VERSION 5.7 ;
  NOWIREEXTENSIONATPIN ON ;
  DIVIDERCHAR "/" ;
  BUSBITCHARS "[]" ;
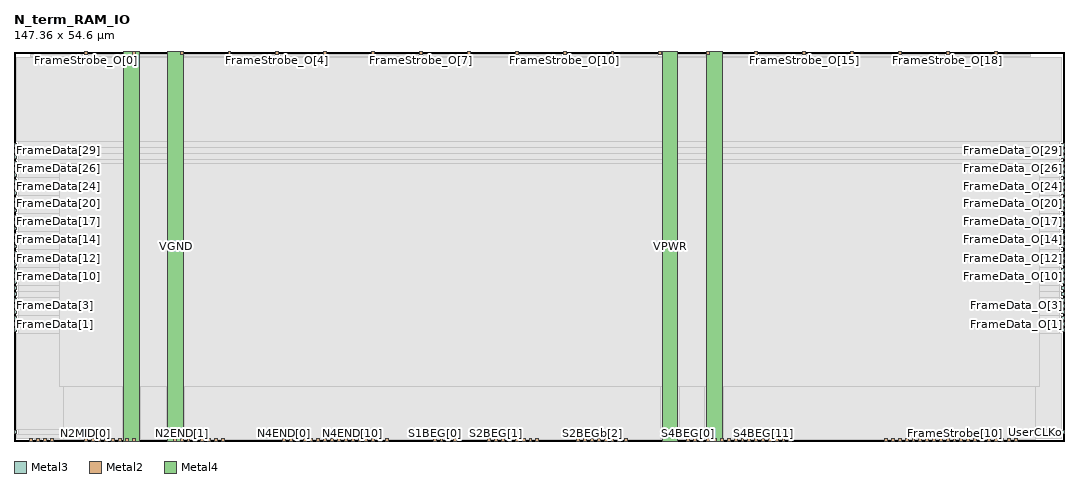
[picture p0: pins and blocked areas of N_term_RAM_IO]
MACRO N_term_RAM_IO
  CLASS BLOCK ;
  FOREIGN N_term_RAM_IO ;
  ORIGIN 0.000 0.000 ;
  SIZE 147.360 BY 54.600 ;
  PIN FrameData[0]
    DIRECTION INPUT ;
    USE SIGNAL ;
    ANTENNAGATEAREA 0.180700 ;
    ANTENNADIFFAREA 2.015400 ;
    PORT
      LAYER Metal3 ;
        RECT 0.000 15.340 0.400 15.740 ;
    END
  END FrameData[0]
  PIN FrameData[10]
    DIRECTION INPUT ;
    USE SIGNAL ;
    ANTENNAGATEAREA 0.180700 ;
    ANTENNADIFFAREA 2.015400 ;
    PORT
      LAYER Metal3 ;
        RECT 0.000 23.740 0.400 24.140 ;
    END
  END FrameData[10]
  PIN FrameData[11]
    DIRECTION INPUT ;
    USE SIGNAL ;
    ANTENNAGATEAREA 0.180700 ;
    ANTENNADIFFAREA 2.015400 ;
    PORT
      LAYER Metal3 ;
        RECT 0.000 24.580 0.400 24.980 ;
    END
  END FrameData[11]
  PIN FrameData[12]
    DIRECTION INPUT ;
    USE SIGNAL ;
    ANTENNAGATEAREA 0.180700 ;
    ANTENNADIFFAREA 2.015400 ;
    PORT
      LAYER Metal3 ;
        RECT 0.000 25.420 0.400 25.820 ;
    END
  END FrameData[12]
  PIN FrameData[13]
    DIRECTION INPUT ;
    USE SIGNAL ;
    ANTENNAGATEAREA 0.180700 ;
    ANTENNADIFFAREA 2.015400 ;
    PORT
      LAYER Metal3 ;
        RECT 0.000 26.260 0.400 26.660 ;
    END
  END FrameData[13]
  PIN FrameData[14]
    DIRECTION INPUT ;
    USE SIGNAL ;
    ANTENNAGATEAREA 0.180700 ;
    ANTENNADIFFAREA 2.015400 ;
    PORT
      LAYER Metal3 ;
        RECT 0.000 27.100 0.400 27.500 ;
    END
  END FrameData[14]
  PIN FrameData[15]
    DIRECTION INPUT ;
    USE SIGNAL ;
    ANTENNAGATEAREA 0.180700 ;
    ANTENNADIFFAREA 2.015400 ;
    PORT
      LAYER Metal3 ;
        RECT 0.000 27.940 0.400 28.340 ;
    END
  END FrameData[15]
  PIN FrameData[16]
    DIRECTION INPUT ;
    USE SIGNAL ;
    ANTENNAGATEAREA 0.180700 ;
    ANTENNADIFFAREA 2.015400 ;
    PORT
      LAYER Metal3 ;
        RECT 0.000 28.780 0.400 29.180 ;
    END
  END FrameData[16]
  PIN FrameData[17]
    DIRECTION INPUT ;
    USE SIGNAL ;
    ANTENNAGATEAREA 0.180700 ;
    ANTENNADIFFAREA 2.015400 ;
    PORT
      LAYER Metal3 ;
        RECT 0.000 29.620 0.400 30.020 ;
    END
  END FrameData[17]
  PIN FrameData[18]
    DIRECTION INPUT ;
    USE SIGNAL ;
    ANTENNAGATEAREA 0.180700 ;
    ANTENNADIFFAREA 2.015400 ;
    PORT
      LAYER Metal3 ;
        RECT 0.000 30.460 0.400 30.860 ;
    END
  END FrameData[18]
  PIN FrameData[19]
    DIRECTION INPUT ;
    USE SIGNAL ;
    ANTENNAGATEAREA 0.180700 ;
    ANTENNADIFFAREA 2.015400 ;
    PORT
      LAYER Metal3 ;
        RECT 0.000 31.300 0.400 31.700 ;
    END
  END FrameData[19]
  PIN FrameData[1]
    DIRECTION INPUT ;
    USE SIGNAL ;
    ANTENNAGATEAREA 0.180700 ;
    ANTENNADIFFAREA 2.015400 ;
    PORT
      LAYER Metal3 ;
        RECT 0.000 16.180 0.400 16.580 ;
    END
  END FrameData[1]
  PIN FrameData[20]
    DIRECTION INPUT ;
    USE SIGNAL ;
    ANTENNAGATEAREA 0.180700 ;
    ANTENNADIFFAREA 2.015400 ;
    PORT
      LAYER Metal3 ;
        RECT 0.000 32.140 0.400 32.540 ;
    END
  END FrameData[20]
  PIN FrameData[21]
    DIRECTION INPUT ;
    USE SIGNAL ;
    ANTENNAGATEAREA 0.180700 ;
    ANTENNADIFFAREA 2.015400 ;
    PORT
      LAYER Metal3 ;
        RECT 0.000 32.980 0.400 33.380 ;
    END
  END FrameData[21]
  PIN FrameData[22]
    DIRECTION INPUT ;
    USE SIGNAL ;
    ANTENNAGATEAREA 0.180700 ;
    ANTENNADIFFAREA 2.015400 ;
    PORT
      LAYER Metal3 ;
        RECT 0.000 33.820 0.400 34.220 ;
    END
  END FrameData[22]
  PIN FrameData[23]
    DIRECTION INPUT ;
    USE SIGNAL ;
    ANTENNAGATEAREA 0.180700 ;
    ANTENNADIFFAREA 2.015400 ;
    PORT
      LAYER Metal3 ;
        RECT 0.000 34.660 0.400 35.060 ;
    END
  END FrameData[23]
  PIN FrameData[24]
    DIRECTION INPUT ;
    USE SIGNAL ;
    ANTENNAGATEAREA 0.180700 ;
    ANTENNADIFFAREA 2.015400 ;
    PORT
      LAYER Metal3 ;
        RECT 0.000 35.500 0.400 35.900 ;
    END
  END FrameData[24]
  PIN FrameData[25]
    DIRECTION INPUT ;
    USE SIGNAL ;
    ANTENNAGATEAREA 0.180700 ;
    ANTENNADIFFAREA 2.015400 ;
    PORT
      LAYER Metal3 ;
        RECT 0.000 36.340 0.400 36.740 ;
    END
  END FrameData[25]
  PIN FrameData[26]
    DIRECTION INPUT ;
    USE SIGNAL ;
    ANTENNAGATEAREA 0.180700 ;
    ANTENNADIFFAREA 2.015400 ;
    PORT
      LAYER Metal3 ;
        RECT 0.000 37.180 0.400 37.580 ;
    END
  END FrameData[26]
  PIN FrameData[27]
    DIRECTION INPUT ;
    USE SIGNAL ;
    ANTENNAGATEAREA 0.180700 ;
    ANTENNADIFFAREA 2.015400 ;
    PORT
      LAYER Metal3 ;
        RECT 0.000 38.020 0.400 38.420 ;
    END
  END FrameData[27]
  PIN FrameData[28]
    DIRECTION INPUT ;
    USE SIGNAL ;
    ANTENNAGATEAREA 0.180700 ;
    ANTENNADIFFAREA 2.015400 ;
    PORT
      LAYER Metal3 ;
        RECT 0.000 38.860 0.400 39.260 ;
    END
  END FrameData[28]
  PIN FrameData[29]
    DIRECTION INPUT ;
    USE SIGNAL ;
    ANTENNAGATEAREA 0.180700 ;
    ANTENNADIFFAREA 2.015400 ;
    PORT
      LAYER Metal3 ;
        RECT 0.000 39.700 0.400 40.100 ;
    END
  END FrameData[29]
  PIN FrameData[2]
    DIRECTION INPUT ;
    USE SIGNAL ;
    ANTENNAGATEAREA 0.180700 ;
    ANTENNADIFFAREA 2.015400 ;
    PORT
      LAYER Metal3 ;
        RECT 0.000 17.020 0.400 17.420 ;
    END
  END FrameData[2]
  PIN FrameData[30]
    DIRECTION INPUT ;
    USE SIGNAL ;
    ANTENNAGATEAREA 0.180700 ;
    ANTENNADIFFAREA 2.015400 ;
    PORT
      LAYER Metal3 ;
        RECT 0.000 40.540 0.400 40.940 ;
    END
  END FrameData[30]
  PIN FrameData[31]
    DIRECTION INPUT ;
    USE SIGNAL ;
    ANTENNAGATEAREA 0.180700 ;
    ANTENNADIFFAREA 2.015400 ;
    PORT
      LAYER Metal3 ;
        RECT 0.000 41.380 0.400 41.780 ;
    END
  END FrameData[31]
  PIN FrameData[3]
    DIRECTION INPUT ;
    USE SIGNAL ;
    ANTENNAGATEAREA 0.180700 ;
    ANTENNADIFFAREA 2.015400 ;
    PORT
      LAYER Metal3 ;
        RECT 0.000 17.860 0.400 18.260 ;
    END
  END FrameData[3]
  PIN FrameData[4]
    DIRECTION INPUT ;
    USE SIGNAL ;
    ANTENNAGATEAREA 0.180700 ;
    ANTENNADIFFAREA 2.015400 ;
    PORT
      LAYER Metal3 ;
        RECT 0.000 18.700 0.400 19.100 ;
    END
  END FrameData[4]
  PIN FrameData[5]
    DIRECTION INPUT ;
    USE SIGNAL ;
    ANTENNAGATEAREA 0.180700 ;
    ANTENNADIFFAREA 2.015400 ;
    PORT
      LAYER Metal3 ;
        RECT 0.000 19.540 0.400 19.940 ;
    END
  END FrameData[5]
  PIN FrameData[6]
    DIRECTION INPUT ;
    USE SIGNAL ;
    ANTENNAGATEAREA 0.180700 ;
    ANTENNADIFFAREA 2.015400 ;
    PORT
      LAYER Metal3 ;
        RECT 0.000 20.380 0.400 20.780 ;
    END
  END FrameData[6]
  PIN FrameData[7]
    DIRECTION INPUT ;
    USE SIGNAL ;
    ANTENNAGATEAREA 0.180700 ;
    ANTENNADIFFAREA 2.015400 ;
    PORT
      LAYER Metal3 ;
        RECT 0.000 21.220 0.400 21.620 ;
    END
  END FrameData[7]
  PIN FrameData[8]
    DIRECTION INPUT ;
    USE SIGNAL ;
    ANTENNAGATEAREA 0.180700 ;
    ANTENNADIFFAREA 2.015400 ;
    PORT
      LAYER Metal3 ;
        RECT 0.000 22.060 0.400 22.460 ;
    END
  END FrameData[8]
  PIN FrameData[9]
    DIRECTION INPUT ;
    USE SIGNAL ;
    ANTENNAGATEAREA 0.180700 ;
    ANTENNADIFFAREA 2.015400 ;
    PORT
      LAYER Metal3 ;
        RECT 0.000 22.900 0.400 23.300 ;
    END
  END FrameData[9]
  PIN FrameData_O[0]
    DIRECTION OUTPUT ;
    USE SIGNAL ;
    ANTENNADIFFAREA 2.724000 ;
    PORT
      LAYER Metal3 ;
        RECT 146.960 15.340 147.360 15.740 ;
    END
  END FrameData_O[0]
  PIN FrameData_O[10]
    DIRECTION OUTPUT ;
    USE SIGNAL ;
    ANTENNADIFFAREA 2.724000 ;
    PORT
      LAYER Metal3 ;
        RECT 146.960 23.740 147.360 24.140 ;
    END
  END FrameData_O[10]
  PIN FrameData_O[11]
    DIRECTION OUTPUT ;
    USE SIGNAL ;
    ANTENNADIFFAREA 2.724000 ;
    PORT
      LAYER Metal3 ;
        RECT 146.960 24.580 147.360 24.980 ;
    END
  END FrameData_O[11]
  PIN FrameData_O[12]
    DIRECTION OUTPUT ;
    USE SIGNAL ;
    ANTENNADIFFAREA 2.724000 ;
    PORT
      LAYER Metal3 ;
        RECT 146.960 25.420 147.360 25.820 ;
    END
  END FrameData_O[12]
  PIN FrameData_O[13]
    DIRECTION OUTPUT ;
    USE SIGNAL ;
    ANTENNADIFFAREA 2.724000 ;
    PORT
      LAYER Metal3 ;
        RECT 146.960 26.260 147.360 26.660 ;
    END
  END FrameData_O[13]
  PIN FrameData_O[14]
    DIRECTION OUTPUT ;
    USE SIGNAL ;
    ANTENNADIFFAREA 2.724000 ;
    PORT
      LAYER Metal3 ;
        RECT 146.960 27.100 147.360 27.500 ;
    END
  END FrameData_O[14]
  PIN FrameData_O[15]
    DIRECTION OUTPUT ;
    USE SIGNAL ;
    ANTENNADIFFAREA 2.724000 ;
    PORT
      LAYER Metal3 ;
        RECT 146.960 27.940 147.360 28.340 ;
    END
  END FrameData_O[15]
  PIN FrameData_O[16]
    DIRECTION OUTPUT ;
    USE SIGNAL ;
    ANTENNADIFFAREA 2.724000 ;
    PORT
      LAYER Metal3 ;
        RECT 146.960 28.780 147.360 29.180 ;
    END
  END FrameData_O[16]
  PIN FrameData_O[17]
    DIRECTION OUTPUT ;
    USE SIGNAL ;
    ANTENNADIFFAREA 2.724000 ;
    PORT
      LAYER Metal3 ;
        RECT 146.960 29.620 147.360 30.020 ;
    END
  END FrameData_O[17]
  PIN FrameData_O[18]
    DIRECTION OUTPUT ;
    USE SIGNAL ;
    ANTENNADIFFAREA 2.724000 ;
    PORT
      LAYER Metal3 ;
        RECT 146.960 30.460 147.360 30.860 ;
    END
  END FrameData_O[18]
  PIN FrameData_O[19]
    DIRECTION OUTPUT ;
    USE SIGNAL ;
    ANTENNADIFFAREA 2.724000 ;
    PORT
      LAYER Metal3 ;
        RECT 146.960 31.300 147.360 31.700 ;
    END
  END FrameData_O[19]
  PIN FrameData_O[1]
    DIRECTION OUTPUT ;
    USE SIGNAL ;
    ANTENNADIFFAREA 2.724000 ;
    PORT
      LAYER Metal3 ;
        RECT 146.960 16.180 147.360 16.580 ;
    END
  END FrameData_O[1]
  PIN FrameData_O[20]
    DIRECTION OUTPUT ;
    USE SIGNAL ;
    ANTENNADIFFAREA 2.724000 ;
    PORT
      LAYER Metal3 ;
        RECT 146.960 32.140 147.360 32.540 ;
    END
  END FrameData_O[20]
  PIN FrameData_O[21]
    DIRECTION OUTPUT ;
    USE SIGNAL ;
    ANTENNADIFFAREA 2.724000 ;
    PORT
      LAYER Metal3 ;
        RECT 146.960 32.980 147.360 33.380 ;
    END
  END FrameData_O[21]
  PIN FrameData_O[22]
    DIRECTION OUTPUT ;
    USE SIGNAL ;
    ANTENNADIFFAREA 2.724000 ;
    PORT
      LAYER Metal3 ;
        RECT 146.960 33.820 147.360 34.220 ;
    END
  END FrameData_O[22]
  PIN FrameData_O[23]
    DIRECTION OUTPUT ;
    USE SIGNAL ;
    ANTENNADIFFAREA 2.724000 ;
    PORT
      LAYER Metal3 ;
        RECT 146.960 34.660 147.360 35.060 ;
    END
  END FrameData_O[23]
  PIN FrameData_O[24]
    DIRECTION OUTPUT ;
    USE SIGNAL ;
    ANTENNADIFFAREA 2.724000 ;
    PORT
      LAYER Metal3 ;
        RECT 146.960 35.500 147.360 35.900 ;
    END
  END FrameData_O[24]
  PIN FrameData_O[25]
    DIRECTION OUTPUT ;
    USE SIGNAL ;
    ANTENNADIFFAREA 2.724000 ;
    PORT
      LAYER Metal3 ;
        RECT 146.960 36.340 147.360 36.740 ;
    END
  END FrameData_O[25]
  PIN FrameData_O[26]
    DIRECTION OUTPUT ;
    USE SIGNAL ;
    ANTENNADIFFAREA 2.724000 ;
    PORT
      LAYER Metal3 ;
        RECT 146.960 37.180 147.360 37.580 ;
    END
  END FrameData_O[26]
  PIN FrameData_O[27]
    DIRECTION OUTPUT ;
    USE SIGNAL ;
    ANTENNADIFFAREA 2.724000 ;
    PORT
      LAYER Metal3 ;
        RECT 146.960 38.020 147.360 38.420 ;
    END
  END FrameData_O[27]
  PIN FrameData_O[28]
    DIRECTION OUTPUT ;
    USE SIGNAL ;
    ANTENNADIFFAREA 2.724000 ;
    PORT
      LAYER Metal3 ;
        RECT 146.960 38.860 147.360 39.260 ;
    END
  END FrameData_O[28]
  PIN FrameData_O[29]
    DIRECTION OUTPUT ;
    USE SIGNAL ;
    ANTENNADIFFAREA 2.724000 ;
    PORT
      LAYER Metal3 ;
        RECT 146.960 39.700 147.360 40.100 ;
    END
  END FrameData_O[29]
  PIN FrameData_O[2]
    DIRECTION OUTPUT ;
    USE SIGNAL ;
    ANTENNADIFFAREA 2.724000 ;
    PORT
      LAYER Metal3 ;
        RECT 146.960 17.020 147.360 17.420 ;
    END
  END FrameData_O[2]
  PIN FrameData_O[30]
    DIRECTION OUTPUT ;
    USE SIGNAL ;
    ANTENNADIFFAREA 2.724000 ;
    PORT
      LAYER Metal3 ;
        RECT 146.960 40.540 147.360 40.940 ;
    END
  END FrameData_O[30]
  PIN FrameData_O[31]
    DIRECTION OUTPUT ;
    USE SIGNAL ;
    ANTENNADIFFAREA 2.724000 ;
    PORT
      LAYER Metal3 ;
        RECT 146.960 41.380 147.360 41.780 ;
    END
  END FrameData_O[31]
  PIN FrameData_O[3]
    DIRECTION OUTPUT ;
    USE SIGNAL ;
    ANTENNADIFFAREA 2.724000 ;
    PORT
      LAYER Metal3 ;
        RECT 146.960 17.860 147.360 18.260 ;
    END
  END FrameData_O[3]
  PIN FrameData_O[4]
    DIRECTION OUTPUT ;
    USE SIGNAL ;
    ANTENNADIFFAREA 2.724000 ;
    PORT
      LAYER Metal3 ;
        RECT 146.960 18.700 147.360 19.100 ;
    END
  END FrameData_O[4]
  PIN FrameData_O[5]
    DIRECTION OUTPUT ;
    USE SIGNAL ;
    ANTENNADIFFAREA 2.724000 ;
    PORT
      LAYER Metal3 ;
        RECT 146.960 19.540 147.360 19.940 ;
    END
  END FrameData_O[5]
  PIN FrameData_O[6]
    DIRECTION OUTPUT ;
    USE SIGNAL ;
    ANTENNADIFFAREA 2.724000 ;
    PORT
      LAYER Metal3 ;
        RECT 146.960 20.380 147.360 20.780 ;
    END
  END FrameData_O[6]
  PIN FrameData_O[7]
    DIRECTION OUTPUT ;
    USE SIGNAL ;
    ANTENNADIFFAREA 2.724000 ;
    PORT
      LAYER Metal3 ;
        RECT 146.960 21.220 147.360 21.620 ;
    END
  END FrameData_O[7]
  PIN FrameData_O[8]
    DIRECTION OUTPUT ;
    USE SIGNAL ;
    ANTENNADIFFAREA 2.724000 ;
    PORT
      LAYER Metal3 ;
        RECT 146.960 22.060 147.360 22.460 ;
    END
  END FrameData_O[8]
  PIN FrameData_O[9]
    DIRECTION OUTPUT ;
    USE SIGNAL ;
    ANTENNADIFFAREA 2.724000 ;
    PORT
      LAYER Metal3 ;
        RECT 146.960 22.900 147.360 23.300 ;
    END
  END FrameData_O[9]
  PIN FrameStrobe[0]
    DIRECTION INPUT ;
    USE SIGNAL ;
    ANTENNAGATEAREA 0.180700 ;
    ANTENNADIFFAREA 2.015400 ;
    PORT
      LAYER Metal2 ;
        RECT 122.200 0.000 122.600 0.400 ;
    END
  END FrameStrobe[0]
  PIN FrameStrobe[10]
    DIRECTION INPUT ;
    USE SIGNAL ;
    ANTENNAGATEAREA 0.180700 ;
    ANTENNADIFFAREA 2.015400 ;
    PORT
      LAYER Metal2 ;
        RECT 131.800 0.000 132.200 0.400 ;
    END
  END FrameStrobe[10]
  PIN FrameStrobe[11]
    DIRECTION INPUT ;
    USE SIGNAL ;
    ANTENNAGATEAREA 0.180700 ;
    ANTENNADIFFAREA 2.015400 ;
    PORT
      LAYER Metal2 ;
        RECT 132.760 0.000 133.160 0.400 ;
    END
  END FrameStrobe[11]
  PIN FrameStrobe[12]
    DIRECTION INPUT ;
    USE SIGNAL ;
    ANTENNAGATEAREA 0.180700 ;
    ANTENNADIFFAREA 2.015400 ;
    PORT
      LAYER Metal2 ;
        RECT 133.720 0.000 134.120 0.400 ;
    END
  END FrameStrobe[12]
  PIN FrameStrobe[13]
    DIRECTION INPUT ;
    USE SIGNAL ;
    ANTENNAGATEAREA 0.180700 ;
    ANTENNADIFFAREA 2.015400 ;
    PORT
      LAYER Metal2 ;
        RECT 134.680 0.000 135.080 0.400 ;
    END
  END FrameStrobe[13]
  PIN FrameStrobe[14]
    DIRECTION INPUT ;
    USE SIGNAL ;
    ANTENNAGATEAREA 0.180700 ;
    ANTENNADIFFAREA 2.015400 ;
    PORT
      LAYER Metal2 ;
        RECT 135.640 0.000 136.040 0.400 ;
    END
  END FrameStrobe[14]
  PIN FrameStrobe[15]
    DIRECTION INPUT ;
    USE SIGNAL ;
    ANTENNAGATEAREA 0.180700 ;
    ANTENNADIFFAREA 2.015400 ;
    PORT
      LAYER Metal2 ;
        RECT 136.600 0.000 137.000 0.400 ;
    END
  END FrameStrobe[15]
  PIN FrameStrobe[16]
    DIRECTION INPUT ;
    USE SIGNAL ;
    ANTENNAGATEAREA 0.180700 ;
    ANTENNADIFFAREA 2.015400 ;
    PORT
      LAYER Metal2 ;
        RECT 137.560 0.000 137.960 0.400 ;
    END
  END FrameStrobe[16]
  PIN FrameStrobe[17]
    DIRECTION INPUT ;
    USE SIGNAL ;
    ANTENNAGATEAREA 0.180700 ;
    ANTENNADIFFAREA 2.015400 ;
    PORT
      LAYER Metal2 ;
        RECT 138.520 0.000 138.920 0.400 ;
    END
  END FrameStrobe[17]
  PIN FrameStrobe[18]
    DIRECTION INPUT ;
    USE SIGNAL ;
    ANTENNAGATEAREA 0.180700 ;
    ANTENNADIFFAREA 2.015400 ;
    PORT
      LAYER Metal2 ;
        RECT 139.480 0.000 139.880 0.400 ;
    END
  END FrameStrobe[18]
  PIN FrameStrobe[19]
    DIRECTION INPUT ;
    USE SIGNAL ;
    ANTENNAGATEAREA 0.180700 ;
    ANTENNADIFFAREA 2.015400 ;
    PORT
      LAYER Metal2 ;
        RECT 140.440 0.000 140.840 0.400 ;
    END
  END FrameStrobe[19]
  PIN FrameStrobe[1]
    DIRECTION INPUT ;
    USE SIGNAL ;
    ANTENNAGATEAREA 0.180700 ;
    ANTENNADIFFAREA 2.015400 ;
    PORT
      LAYER Metal2 ;
        RECT 123.160 0.000 123.560 0.400 ;
    END
  END FrameStrobe[1]
  PIN FrameStrobe[2]
    DIRECTION INPUT ;
    USE SIGNAL ;
    ANTENNAGATEAREA 0.180700 ;
    ANTENNADIFFAREA 2.015400 ;
    PORT
      LAYER Metal2 ;
        RECT 124.120 0.000 124.520 0.400 ;
    END
  END FrameStrobe[2]
  PIN FrameStrobe[3]
    DIRECTION INPUT ;
    USE SIGNAL ;
    ANTENNAGATEAREA 0.180700 ;
    ANTENNADIFFAREA 2.015400 ;
    PORT
      LAYER Metal2 ;
        RECT 125.080 0.000 125.480 0.400 ;
    END
  END FrameStrobe[3]
  PIN FrameStrobe[4]
    DIRECTION INPUT ;
    USE SIGNAL ;
    ANTENNAGATEAREA 0.180700 ;
    ANTENNADIFFAREA 2.015400 ;
    PORT
      LAYER Metal2 ;
        RECT 126.040 0.000 126.440 0.400 ;
    END
  END FrameStrobe[4]
  PIN FrameStrobe[5]
    DIRECTION INPUT ;
    USE SIGNAL ;
    ANTENNAGATEAREA 0.180700 ;
    ANTENNADIFFAREA 2.015400 ;
    PORT
      LAYER Metal2 ;
        RECT 127.000 0.000 127.400 0.400 ;
    END
  END FrameStrobe[5]
  PIN FrameStrobe[6]
    DIRECTION INPUT ;
    USE SIGNAL ;
    ANTENNAGATEAREA 0.180700 ;
    ANTENNADIFFAREA 2.015400 ;
    PORT
      LAYER Metal2 ;
        RECT 127.960 0.000 128.360 0.400 ;
    END
  END FrameStrobe[6]
  PIN FrameStrobe[7]
    DIRECTION INPUT ;
    USE SIGNAL ;
    ANTENNAGATEAREA 0.180700 ;
    ANTENNADIFFAREA 2.015400 ;
    PORT
      LAYER Metal2 ;
        RECT 128.920 0.000 129.320 0.400 ;
    END
  END FrameStrobe[7]
  PIN FrameStrobe[8]
    DIRECTION INPUT ;
    USE SIGNAL ;
    ANTENNAGATEAREA 0.180700 ;
    ANTENNADIFFAREA 2.015400 ;
    PORT
      LAYER Metal2 ;
        RECT 129.880 0.000 130.280 0.400 ;
    END
  END FrameStrobe[8]
  PIN FrameStrobe[9]
    DIRECTION INPUT ;
    USE SIGNAL ;
    ANTENNAGATEAREA 0.180700 ;
    ANTENNADIFFAREA 2.015400 ;
    PORT
      LAYER Metal2 ;
        RECT 130.840 0.000 131.240 0.400 ;
    END
  END FrameStrobe[9]
  PIN FrameStrobe_O[0]
    DIRECTION OUTPUT ;
    USE SIGNAL ;
    ANTENNADIFFAREA 2.724000 ;
    PORT
      LAYER Metal2 ;
        RECT 9.880 54.200 10.280 54.600 ;
    END
  END FrameStrobe_O[0]
  PIN FrameStrobe_O[10]
    DIRECTION OUTPUT ;
    USE SIGNAL ;
    ANTENNADIFFAREA 2.724000 ;
    PORT
      LAYER Metal2 ;
        RECT 77.080 54.200 77.480 54.600 ;
    END
  END FrameStrobe_O[10]
  PIN FrameStrobe_O[11]
    DIRECTION OUTPUT ;
    USE SIGNAL ;
    ANTENNADIFFAREA 2.724000 ;
    PORT
      LAYER Metal2 ;
        RECT 83.800 54.200 84.200 54.600 ;
    END
  END FrameStrobe_O[11]
  PIN FrameStrobe_O[12]
    DIRECTION OUTPUT ;
    USE SIGNAL ;
    ANTENNADIFFAREA 2.724000 ;
    PORT
      LAYER Metal2 ;
        RECT 90.520 54.200 90.920 54.600 ;
    END
  END FrameStrobe_O[12]
  PIN FrameStrobe_O[13]
    DIRECTION OUTPUT ;
    USE SIGNAL ;
    ANTENNADIFFAREA 2.724000 ;
    PORT
      LAYER Metal2 ;
        RECT 97.240 54.200 97.640 54.600 ;
    END
  END FrameStrobe_O[13]
  PIN FrameStrobe_O[14]
    DIRECTION OUTPUT ;
    USE SIGNAL ;
    ANTENNADIFFAREA 2.724000 ;
    PORT
      LAYER Metal2 ;
        RECT 103.960 54.200 104.360 54.600 ;
    END
  END FrameStrobe_O[14]
  PIN FrameStrobe_O[15]
    DIRECTION OUTPUT ;
    USE SIGNAL ;
    ANTENNADIFFAREA 2.724000 ;
    PORT
      LAYER Metal2 ;
        RECT 110.680 54.200 111.080 54.600 ;
    END
  END FrameStrobe_O[15]
  PIN FrameStrobe_O[16]
    DIRECTION OUTPUT ;
    USE SIGNAL ;
    ANTENNADIFFAREA 2.724000 ;
    PORT
      LAYER Metal2 ;
        RECT 117.400 54.200 117.800 54.600 ;
    END
  END FrameStrobe_O[16]
  PIN FrameStrobe_O[17]
    DIRECTION OUTPUT ;
    USE SIGNAL ;
    ANTENNADIFFAREA 2.724000 ;
    PORT
      LAYER Metal2 ;
        RECT 124.120 54.200 124.520 54.600 ;
    END
  END FrameStrobe_O[17]
  PIN FrameStrobe_O[18]
    DIRECTION OUTPUT ;
    USE SIGNAL ;
    ANTENNADIFFAREA 2.724000 ;
    PORT
      LAYER Metal2 ;
        RECT 130.840 54.200 131.240 54.600 ;
    END
  END FrameStrobe_O[18]
  PIN FrameStrobe_O[19]
    DIRECTION OUTPUT ;
    USE SIGNAL ;
    ANTENNADIFFAREA 2.724000 ;
    PORT
      LAYER Metal2 ;
        RECT 137.560 54.200 137.960 54.600 ;
    END
  END FrameStrobe_O[19]
  PIN FrameStrobe_O[1]
    DIRECTION OUTPUT ;
    USE SIGNAL ;
    ANTENNADIFFAREA 2.724000 ;
    PORT
      LAYER Metal2 ;
        RECT 16.600 54.200 17.000 54.600 ;
    END
  END FrameStrobe_O[1]
  PIN FrameStrobe_O[2]
    DIRECTION OUTPUT ;
    USE SIGNAL ;
    ANTENNADIFFAREA 2.724000 ;
    PORT
      LAYER Metal2 ;
        RECT 23.320 54.200 23.720 54.600 ;
    END
  END FrameStrobe_O[2]
  PIN FrameStrobe_O[3]
    DIRECTION OUTPUT ;
    USE SIGNAL ;
    ANTENNADIFFAREA 2.724000 ;
    PORT
      LAYER Metal2 ;
        RECT 30.040 54.200 30.440 54.600 ;
    END
  END FrameStrobe_O[3]
  PIN FrameStrobe_O[4]
    DIRECTION OUTPUT ;
    USE SIGNAL ;
    ANTENNADIFFAREA 2.724000 ;
    PORT
      LAYER Metal2 ;
        RECT 36.760 54.200 37.160 54.600 ;
    END
  END FrameStrobe_O[4]
  PIN FrameStrobe_O[5]
    DIRECTION OUTPUT ;
    USE SIGNAL ;
    ANTENNADIFFAREA 2.724000 ;
    PORT
      LAYER Metal2 ;
        RECT 43.480 54.200 43.880 54.600 ;
    END
  END FrameStrobe_O[5]
  PIN FrameStrobe_O[6]
    DIRECTION OUTPUT ;
    USE SIGNAL ;
    ANTENNADIFFAREA 2.724000 ;
    PORT
      LAYER Metal2 ;
        RECT 50.200 54.200 50.600 54.600 ;
    END
  END FrameStrobe_O[6]
  PIN FrameStrobe_O[7]
    DIRECTION OUTPUT ;
    USE SIGNAL ;
    ANTENNADIFFAREA 2.724000 ;
    PORT
      LAYER Metal2 ;
        RECT 56.920 54.200 57.320 54.600 ;
    END
  END FrameStrobe_O[7]
  PIN FrameStrobe_O[8]
    DIRECTION OUTPUT ;
    USE SIGNAL ;
    ANTENNADIFFAREA 2.724000 ;
    PORT
      LAYER Metal2 ;
        RECT 63.640 54.200 64.040 54.600 ;
    END
  END FrameStrobe_O[8]
  PIN FrameStrobe_O[9]
    DIRECTION OUTPUT ;
    USE SIGNAL ;
    ANTENNADIFFAREA 2.724000 ;
    PORT
      LAYER Metal2 ;
        RECT 70.360 54.200 70.760 54.600 ;
    END
  END FrameStrobe_O[9]
  PIN N1END[0]
    DIRECTION INPUT ;
    USE SIGNAL ;
    ANTENNAGATEAREA 0.180700 ;
    ANTENNADIFFAREA 2.015400 ;
    PORT
      LAYER Metal2 ;
        RECT 2.200 0.000 2.600 0.400 ;
    END
  END N1END[0]
  PIN N1END[1]
    DIRECTION INPUT ;
    USE SIGNAL ;
    ANTENNAGATEAREA 0.180700 ;
    ANTENNADIFFAREA 2.015400 ;
    PORT
      LAYER Metal2 ;
        RECT 3.160 0.000 3.560 0.400 ;
    END
  END N1END[1]
  PIN N1END[2]
    DIRECTION INPUT ;
    USE SIGNAL ;
    ANTENNAGATEAREA 0.180700 ;
    ANTENNADIFFAREA 2.015400 ;
    PORT
      LAYER Metal2 ;
        RECT 4.120 0.000 4.520 0.400 ;
    END
  END N1END[2]
  PIN N1END[3]
    DIRECTION INPUT ;
    USE SIGNAL ;
    ANTENNAGATEAREA 0.180700 ;
    ANTENNADIFFAREA 2.015400 ;
    PORT
      LAYER Metal2 ;
        RECT 5.080 0.000 5.480 0.400 ;
    END
  END N1END[3]
  PIN N2END[0]
    DIRECTION INPUT ;
    USE SIGNAL ;
    ANTENNAGATEAREA 0.180700 ;
    ANTENNADIFFAREA 2.015400 ;
    PORT
      LAYER Metal2 ;
        RECT 22.360 0.000 22.760 0.400 ;
    END
  END N2END[0]
  PIN N2END[1]
    DIRECTION INPUT ;
    USE SIGNAL ;
    ANTENNAGATEAREA 0.180700 ;
    ANTENNADIFFAREA 2.015400 ;
    PORT
      LAYER Metal2 ;
        RECT 23.320 0.000 23.720 0.400 ;
    END
  END N2END[1]
  PIN N2END[2]
    DIRECTION INPUT ;
    USE SIGNAL ;
    ANTENNAGATEAREA 0.180700 ;
    ANTENNADIFFAREA 2.015400 ;
    PORT
      LAYER Metal2 ;
        RECT 24.280 0.000 24.680 0.400 ;
    END
  END N2END[2]
  PIN N2END[3]
    DIRECTION INPUT ;
    USE SIGNAL ;
    ANTENNAGATEAREA 0.180700 ;
    ANTENNADIFFAREA 2.015400 ;
    PORT
      LAYER Metal2 ;
        RECT 25.240 0.000 25.640 0.400 ;
    END
  END N2END[3]
  PIN N2END[4]
    DIRECTION INPUT ;
    USE SIGNAL ;
    ANTENNAGATEAREA 0.180700 ;
    ANTENNADIFFAREA 2.015400 ;
    PORT
      LAYER Metal2 ;
        RECT 26.200 0.000 26.600 0.400 ;
    END
  END N2END[4]
  PIN N2END[5]
    DIRECTION INPUT ;
    USE SIGNAL ;
    ANTENNAGATEAREA 0.180700 ;
    ANTENNADIFFAREA 2.015400 ;
    PORT
      LAYER Metal2 ;
        RECT 27.160 0.000 27.560 0.400 ;
    END
  END N2END[5]
  PIN N2END[6]
    DIRECTION INPUT ;
    USE SIGNAL ;
    ANTENNAGATEAREA 0.180700 ;
    ANTENNADIFFAREA 2.015400 ;
    PORT
      LAYER Metal2 ;
        RECT 28.120 0.000 28.520 0.400 ;
    END
  END N2END[6]
  PIN N2END[7]
    DIRECTION INPUT ;
    USE SIGNAL ;
    ANTENNAGATEAREA 0.180700 ;
    ANTENNADIFFAREA 2.015400 ;
    PORT
      LAYER Metal2 ;
        RECT 29.080 0.000 29.480 0.400 ;
    END
  END N2END[7]
  PIN N2MID[0]
    DIRECTION INPUT ;
    USE SIGNAL ;
    ANTENNAGATEAREA 0.180700 ;
    ANTENNADIFFAREA 2.015400 ;
    PORT
      LAYER Metal2 ;
        RECT 9.880 0.000 10.280 0.400 ;
    END
  END N2MID[0]
  PIN N2MID[1]
    DIRECTION INPUT ;
    USE SIGNAL ;
    ANTENNAGATEAREA 0.180700 ;
    ANTENNADIFFAREA 2.015400 ;
    PORT
      LAYER Metal2 ;
        RECT 10.840 0.000 11.240 0.400 ;
    END
  END N2MID[1]
  PIN N2MID[2]
    DIRECTION INPUT ;
    USE SIGNAL ;
    ANTENNAGATEAREA 0.180700 ;
    ANTENNADIFFAREA 2.015400 ;
    PORT
      LAYER Metal2 ;
        RECT 11.800 0.000 12.200 0.400 ;
    END
  END N2MID[2]
  PIN N2MID[3]
    DIRECTION INPUT ;
    USE SIGNAL ;
    ANTENNAGATEAREA 0.180700 ;
    ANTENNADIFFAREA 2.015400 ;
    PORT
      LAYER Metal2 ;
        RECT 12.760 0.000 13.160 0.400 ;
    END
  END N2MID[3]
  PIN N2MID[4]
    DIRECTION INPUT ;
    USE SIGNAL ;
    ANTENNAGATEAREA 0.180700 ;
    ANTENNADIFFAREA 2.015400 ;
    PORT
      LAYER Metal2 ;
        RECT 13.720 0.000 14.120 0.400 ;
    END
  END N2MID[4]
  PIN N2MID[5]
    DIRECTION INPUT ;
    USE SIGNAL ;
    ANTENNAGATEAREA 0.180700 ;
    ANTENNADIFFAREA 2.015400 ;
    PORT
      LAYER Metal2 ;
        RECT 14.680 0.000 15.080 0.400 ;
    END
  END N2MID[5]
  PIN N2MID[6]
    DIRECTION INPUT ;
    USE SIGNAL ;
    ANTENNAGATEAREA 0.180700 ;
    ANTENNADIFFAREA 2.015400 ;
    PORT
      LAYER Metal2 ;
        RECT 15.640 0.000 16.040 0.400 ;
    END
  END N2MID[6]
  PIN N2MID[7]
    DIRECTION INPUT ;
    USE SIGNAL ;
    ANTENNAGATEAREA 0.180700 ;
    ANTENNADIFFAREA 2.015400 ;
    PORT
      LAYER Metal2 ;
        RECT 16.600 0.000 17.000 0.400 ;
    END
  END N2MID[7]
  PIN N4END[0]
    DIRECTION INPUT ;
    USE SIGNAL ;
    ANTENNAGATEAREA 0.180700 ;
    ANTENNADIFFAREA 2.015400 ;
    PORT
      LAYER Metal2 ;
        RECT 37.720 0.000 38.120 0.400 ;
    END
  END N4END[0]
  PIN N4END[10]
    DIRECTION INPUT ;
    USE SIGNAL ;
    ANTENNAGATEAREA 0.180700 ;
    ANTENNADIFFAREA 2.015400 ;
    PORT
      LAYER Metal2 ;
        RECT 47.320 0.000 47.720 0.400 ;
    END
  END N4END[10]
  PIN N4END[11]
    DIRECTION INPUT ;
    USE SIGNAL ;
    ANTENNAGATEAREA 0.180700 ;
    ANTENNADIFFAREA 2.015400 ;
    PORT
      LAYER Metal2 ;
        RECT 48.280 0.000 48.680 0.400 ;
    END
  END N4END[11]
  PIN N4END[12]
    DIRECTION INPUT ;
    USE SIGNAL ;
    ANTENNAGATEAREA 0.180700 ;
    ANTENNADIFFAREA 2.015400 ;
    PORT
      LAYER Metal2 ;
        RECT 49.240 0.000 49.640 0.400 ;
    END
  END N4END[12]
  PIN N4END[13]
    DIRECTION INPUT ;
    USE SIGNAL ;
    ANTENNAGATEAREA 0.180700 ;
    ANTENNADIFFAREA 2.015400 ;
    PORT
      LAYER Metal2 ;
        RECT 50.200 0.000 50.600 0.400 ;
    END
  END N4END[13]
  PIN N4END[14]
    DIRECTION INPUT ;
    USE SIGNAL ;
    ANTENNAGATEAREA 0.180700 ;
    ANTENNADIFFAREA 2.015400 ;
    PORT
      LAYER Metal2 ;
        RECT 51.160 0.000 51.560 0.400 ;
    END
  END N4END[14]
  PIN N4END[15]
    DIRECTION INPUT ;
    USE SIGNAL ;
    ANTENNAGATEAREA 0.180700 ;
    ANTENNADIFFAREA 2.015400 ;
    PORT
      LAYER Metal2 ;
        RECT 52.120 0.000 52.520 0.400 ;
    END
  END N4END[15]
  PIN N4END[1]
    DIRECTION INPUT ;
    USE SIGNAL ;
    ANTENNAGATEAREA 0.180700 ;
    ANTENNADIFFAREA 2.015400 ;
    PORT
      LAYER Metal2 ;
        RECT 38.680 0.000 39.080 0.400 ;
    END
  END N4END[1]
  PIN N4END[2]
    DIRECTION INPUT ;
    USE SIGNAL ;
    ANTENNAGATEAREA 0.180700 ;
    ANTENNADIFFAREA 2.015400 ;
    PORT
      LAYER Metal2 ;
        RECT 39.640 0.000 40.040 0.400 ;
    END
  END N4END[2]
  PIN N4END[3]
    DIRECTION INPUT ;
    USE SIGNAL ;
    ANTENNAGATEAREA 0.180700 ;
    ANTENNADIFFAREA 2.015400 ;
    PORT
      LAYER Metal2 ;
        RECT 40.600 0.000 41.000 0.400 ;
    END
  END N4END[3]
  PIN N4END[4]
    DIRECTION INPUT ;
    USE SIGNAL ;
    ANTENNAGATEAREA 0.180700 ;
    ANTENNADIFFAREA 2.015400 ;
    PORT
      LAYER Metal2 ;
        RECT 41.560 0.000 41.960 0.400 ;
    END
  END N4END[4]
  PIN N4END[5]
    DIRECTION INPUT ;
    USE SIGNAL ;
    ANTENNAGATEAREA 0.180700 ;
    ANTENNADIFFAREA 2.015400 ;
    PORT
      LAYER Metal2 ;
        RECT 42.520 0.000 42.920 0.400 ;
    END
  END N4END[5]
  PIN N4END[6]
    DIRECTION INPUT ;
    USE SIGNAL ;
    ANTENNAGATEAREA 0.180700 ;
    ANTENNADIFFAREA 2.015400 ;
    PORT
      LAYER Metal2 ;
        RECT 43.480 0.000 43.880 0.400 ;
    END
  END N4END[6]
  PIN N4END[7]
    DIRECTION INPUT ;
    USE SIGNAL ;
    ANTENNAGATEAREA 0.180700 ;
    ANTENNADIFFAREA 2.015400 ;
    PORT
      LAYER Metal2 ;
        RECT 44.440 0.000 44.840 0.400 ;
    END
  END N4END[7]
  PIN N4END[8]
    DIRECTION INPUT ;
    USE SIGNAL ;
    ANTENNAGATEAREA 0.180700 ;
    ANTENNADIFFAREA 2.015400 ;
    PORT
      LAYER Metal2 ;
        RECT 45.400 0.000 45.800 0.400 ;
    END
  END N4END[8]
  PIN N4END[9]
    DIRECTION INPUT ;
    USE SIGNAL ;
    ANTENNAGATEAREA 0.180700 ;
    ANTENNADIFFAREA 2.015400 ;
    PORT
      LAYER Metal2 ;
        RECT 46.360 0.000 46.760 0.400 ;
    END
  END N4END[9]
  PIN S1BEG[0]
    DIRECTION OUTPUT ;
    USE SIGNAL ;
    ANTENNADIFFAREA 2.724000 ;
    PORT
      LAYER Metal2 ;
        RECT 58.840 0.000 59.240 0.400 ;
    END
  END S1BEG[0]
  PIN S1BEG[1]
    DIRECTION OUTPUT ;
    USE SIGNAL ;
    ANTENNADIFFAREA 2.724000 ;
    PORT
      LAYER Metal2 ;
        RECT 59.800 0.000 60.200 0.400 ;
    END
  END S1BEG[1]
  PIN S1BEG[2]
    DIRECTION OUTPUT ;
    USE SIGNAL ;
    ANTENNADIFFAREA 2.724000 ;
    PORT
      LAYER Metal2 ;
        RECT 60.760 0.000 61.160 0.400 ;
    END
  END S1BEG[2]
  PIN S1BEG[3]
    DIRECTION OUTPUT ;
    USE SIGNAL ;
    ANTENNADIFFAREA 2.724000 ;
    PORT
      LAYER Metal2 ;
        RECT 61.720 0.000 62.120 0.400 ;
    END
  END S1BEG[3]
  PIN S2BEG[0]
    DIRECTION OUTPUT ;
    USE SIGNAL ;
    ANTENNADIFFAREA 2.724000 ;
    PORT
      LAYER Metal2 ;
        RECT 66.520 0.000 66.920 0.400 ;
    END
  END S2BEG[0]
  PIN S2BEG[1]
    DIRECTION OUTPUT ;
    USE SIGNAL ;
    ANTENNADIFFAREA 2.724000 ;
    PORT
      LAYER Metal2 ;
        RECT 67.480 0.000 67.880 0.400 ;
    END
  END S2BEG[1]
  PIN S2BEG[2]
    DIRECTION OUTPUT ;
    USE SIGNAL ;
    ANTENNADIFFAREA 2.724000 ;
    PORT
      LAYER Metal2 ;
        RECT 68.440 0.000 68.840 0.400 ;
    END
  END S2BEG[2]
  PIN S2BEG[3]
    DIRECTION OUTPUT ;
    USE SIGNAL ;
    ANTENNADIFFAREA 2.724000 ;
    PORT
      LAYER Metal2 ;
        RECT 69.400 0.000 69.800 0.400 ;
    END
  END S2BEG[3]
  PIN S2BEG[4]
    DIRECTION OUTPUT ;
    USE SIGNAL ;
    ANTENNADIFFAREA 2.724000 ;
    PORT
      LAYER Metal2 ;
        RECT 70.360 0.000 70.760 0.400 ;
    END
  END S2BEG[4]
  PIN S2BEG[5]
    DIRECTION OUTPUT ;
    USE SIGNAL ;
    ANTENNADIFFAREA 2.724000 ;
    PORT
      LAYER Metal2 ;
        RECT 71.320 0.000 71.720 0.400 ;
    END
  END S2BEG[5]
  PIN S2BEG[6]
    DIRECTION OUTPUT ;
    USE SIGNAL ;
    ANTENNADIFFAREA 2.724000 ;
    PORT
      LAYER Metal2 ;
        RECT 72.280 0.000 72.680 0.400 ;
    END
  END S2BEG[6]
  PIN S2BEG[7]
    DIRECTION OUTPUT ;
    USE SIGNAL ;
    ANTENNADIFFAREA 2.724000 ;
    PORT
      LAYER Metal2 ;
        RECT 73.240 0.000 73.640 0.400 ;
    END
  END S2BEG[7]
  PIN S2BEGb[0]
    DIRECTION OUTPUT ;
    USE SIGNAL ;
    ANTENNADIFFAREA 2.724000 ;
    PORT
      LAYER Metal2 ;
        RECT 79.000 0.000 79.400 0.400 ;
    END
  END S2BEGb[0]
  PIN S2BEGb[1]
    DIRECTION OUTPUT ;
    USE SIGNAL ;
    ANTENNADIFFAREA 2.724000 ;
    PORT
      LAYER Metal2 ;
        RECT 79.960 0.000 80.360 0.400 ;
    END
  END S2BEGb[1]
  PIN S2BEGb[2]
    DIRECTION OUTPUT ;
    USE SIGNAL ;
    ANTENNADIFFAREA 2.724000 ;
    PORT
      LAYER Metal2 ;
        RECT 80.920 0.000 81.320 0.400 ;
    END
  END S2BEGb[2]
  PIN S2BEGb[3]
    DIRECTION OUTPUT ;
    USE SIGNAL ;
    ANTENNADIFFAREA 2.724000 ;
    PORT
      LAYER Metal2 ;
        RECT 81.880 0.000 82.280 0.400 ;
    END
  END S2BEGb[3]
  PIN S2BEGb[4]
    DIRECTION OUTPUT ;
    USE SIGNAL ;
    ANTENNADIFFAREA 2.724000 ;
    PORT
      LAYER Metal2 ;
        RECT 82.840 0.000 83.240 0.400 ;
    END
  END S2BEGb[4]
  PIN S2BEGb[5]
    DIRECTION OUTPUT ;
    USE SIGNAL ;
    ANTENNADIFFAREA 2.724000 ;
    PORT
      LAYER Metal2 ;
        RECT 83.800 0.000 84.200 0.400 ;
    END
  END S2BEGb[5]
  PIN S2BEGb[6]
    DIRECTION OUTPUT ;
    USE SIGNAL ;
    ANTENNADIFFAREA 2.724000 ;
    PORT
      LAYER Metal2 ;
        RECT 84.760 0.000 85.160 0.400 ;
    END
  END S2BEGb[6]
  PIN S2BEGb[7]
    DIRECTION OUTPUT ;
    USE SIGNAL ;
    ANTENNADIFFAREA 2.724000 ;
    PORT
      LAYER Metal2 ;
        RECT 85.720 0.000 86.120 0.400 ;
    END
  END S2BEGb[7]
  PIN S4BEG[0]
    DIRECTION OUTPUT ;
    USE SIGNAL ;
    ANTENNADIFFAREA 2.724000 ;
    PORT
      LAYER Metal2 ;
        RECT 94.360 0.000 94.760 0.400 ;
    END
  END S4BEG[0]
  PIN S4BEG[10]
    DIRECTION OUTPUT ;
    USE SIGNAL ;
    ANTENNADIFFAREA 2.724000 ;
    PORT
      LAYER Metal2 ;
        RECT 103.960 0.000 104.360 0.400 ;
    END
  END S4BEG[10]
  PIN S4BEG[11]
    DIRECTION OUTPUT ;
    USE SIGNAL ;
    ANTENNADIFFAREA 2.724000 ;
    PORT
      LAYER Metal2 ;
        RECT 104.920 0.000 105.320 0.400 ;
    END
  END S4BEG[11]
  PIN S4BEG[12]
    DIRECTION OUTPUT ;
    USE SIGNAL ;
    ANTENNADIFFAREA 2.724000 ;
    PORT
      LAYER Metal2 ;
        RECT 105.880 0.000 106.280 0.400 ;
    END
  END S4BEG[12]
  PIN S4BEG[13]
    DIRECTION OUTPUT ;
    USE SIGNAL ;
    ANTENNADIFFAREA 2.724000 ;
    PORT
      LAYER Metal2 ;
        RECT 106.840 0.000 107.240 0.400 ;
    END
  END S4BEG[13]
  PIN S4BEG[14]
    DIRECTION OUTPUT ;
    USE SIGNAL ;
    ANTENNADIFFAREA 2.724000 ;
    PORT
      LAYER Metal2 ;
        RECT 107.800 0.000 108.200 0.400 ;
    END
  END S4BEG[14]
  PIN S4BEG[15]
    DIRECTION OUTPUT ;
    USE SIGNAL ;
    ANTENNADIFFAREA 2.724000 ;
    PORT
      LAYER Metal2 ;
        RECT 108.760 0.000 109.160 0.400 ;
    END
  END S4BEG[15]
  PIN S4BEG[1]
    DIRECTION OUTPUT ;
    USE SIGNAL ;
    ANTENNADIFFAREA 2.724000 ;
    PORT
      LAYER Metal2 ;
        RECT 95.320 0.000 95.720 0.400 ;
    END
  END S4BEG[1]
  PIN S4BEG[2]
    DIRECTION OUTPUT ;
    USE SIGNAL ;
    ANTENNADIFFAREA 2.724000 ;
    PORT
      LAYER Metal2 ;
        RECT 96.280 0.000 96.680 0.400 ;
    END
  END S4BEG[2]
  PIN S4BEG[3]
    DIRECTION OUTPUT ;
    USE SIGNAL ;
    ANTENNADIFFAREA 2.724000 ;
    PORT
      LAYER Metal2 ;
        RECT 97.240 0.000 97.640 0.400 ;
    END
  END S4BEG[3]
  PIN S4BEG[4]
    DIRECTION OUTPUT ;
    USE SIGNAL ;
    ANTENNADIFFAREA 2.724000 ;
    PORT
      LAYER Metal2 ;
        RECT 98.200 0.000 98.600 0.400 ;
    END
  END S4BEG[4]
  PIN S4BEG[5]
    DIRECTION OUTPUT ;
    USE SIGNAL ;
    ANTENNADIFFAREA 2.724000 ;
    PORT
      LAYER Metal2 ;
        RECT 99.160 0.000 99.560 0.400 ;
    END
  END S4BEG[5]
  PIN S4BEG[6]
    DIRECTION OUTPUT ;
    USE SIGNAL ;
    ANTENNADIFFAREA 2.724000 ;
    PORT
      LAYER Metal2 ;
        RECT 100.120 0.000 100.520 0.400 ;
    END
  END S4BEG[6]
  PIN S4BEG[7]
    DIRECTION OUTPUT ;
    USE SIGNAL ;
    ANTENNADIFFAREA 2.724000 ;
    PORT
      LAYER Metal2 ;
        RECT 101.080 0.000 101.480 0.400 ;
    END
  END S4BEG[7]
  PIN S4BEG[8]
    DIRECTION OUTPUT ;
    USE SIGNAL ;
    ANTENNADIFFAREA 2.724000 ;
    PORT
      LAYER Metal2 ;
        RECT 102.040 0.000 102.440 0.400 ;
    END
  END S4BEG[8]
  PIN S4BEG[9]
    DIRECTION OUTPUT ;
    USE SIGNAL ;
    ANTENNADIFFAREA 2.724000 ;
    PORT
      LAYER Metal2 ;
        RECT 103.000 0.000 103.400 0.400 ;
    END
  END S4BEG[9]
  PIN UserCLK
    DIRECTION INPUT ;
    USE SIGNAL ;
    ANTENNAGATEAREA 0.725400 ;
    PORT
      LAYER Metal3 ;
        RECT 0.000 1.060 0.400 1.460 ;
    END
  END UserCLK
  PIN UserCLKo
    DIRECTION OUTPUT ;
    USE SIGNAL ;
    ANTENNADIFFAREA 2.724000 ;
    PORT
      LAYER Metal3 ;
        RECT 146.960 1.060 147.360 1.460 ;
    END
  END UserCLKo
  PIN VGND
    DIRECTION INOUT ;
    USE GROUND ;
    PORT
      LAYER Metal4 ;
        RECT 21.580 0.000 23.780 54.600 ;
    END
    PORT
      LAYER Metal4 ;
        RECT 97.180 0.000 99.380 54.600 ;
    END
  END VGND
  PIN VPWR
    DIRECTION INOUT ;
    USE POWER ;
    PORT
      LAYER Metal4 ;
        RECT 15.380 0.000 17.580 54.600 ;
    END
    PORT
      LAYER Metal4 ;
        RECT 90.980 0.000 93.180 54.600 ;
    END
  END VPWR
  OBS
      LAYER GatPoly ;
        RECT 2.880 3.630 144.480 49.290 ;
      LAYER Metal1 ;
        RECT 2.880 3.560 144.480 49.360 ;
      LAYER Metal2 ;
        RECT 2.295 53.990 9.670 54.200 ;
        RECT 10.490 53.990 16.390 54.200 ;
        RECT 17.210 53.990 23.110 54.200 ;
        RECT 23.930 53.990 29.830 54.200 ;
        RECT 30.650 53.990 36.550 54.200 ;
        RECT 37.370 53.990 43.270 54.200 ;
        RECT 44.090 53.990 49.990 54.200 ;
        RECT 50.810 53.990 56.710 54.200 ;
        RECT 57.530 53.990 63.430 54.200 ;
        RECT 64.250 53.990 70.150 54.200 ;
        RECT 70.970 53.990 76.870 54.200 ;
        RECT 77.690 53.990 83.590 54.200 ;
        RECT 84.410 53.990 90.310 54.200 ;
        RECT 91.130 53.990 97.030 54.200 ;
        RECT 97.850 53.990 103.750 54.200 ;
        RECT 104.570 53.990 110.470 54.200 ;
        RECT 111.290 53.990 117.190 54.200 ;
        RECT 118.010 53.990 123.910 54.200 ;
        RECT 124.730 53.990 130.630 54.200 ;
        RECT 131.450 53.990 137.350 54.200 ;
        RECT 138.170 53.990 142.665 54.200 ;
        RECT 2.295 0.610 142.665 53.990 ;
        RECT 2.810 0.275 2.950 0.610 ;
        RECT 3.770 0.275 3.910 0.610 ;
        RECT 4.730 0.275 4.870 0.610 ;
        RECT 5.690 0.275 9.670 0.610 ;
        RECT 10.490 0.275 10.630 0.610 ;
        RECT 11.450 0.275 11.590 0.610 ;
        RECT 12.410 0.275 12.550 0.610 ;
        RECT 13.370 0.275 13.510 0.610 ;
        RECT 14.330 0.275 14.470 0.610 ;
        RECT 15.290 0.275 15.430 0.610 ;
        RECT 16.250 0.275 16.390 0.610 ;
        RECT 17.210 0.275 22.150 0.610 ;
        RECT 22.970 0.275 23.110 0.610 ;
        RECT 23.930 0.275 24.070 0.610 ;
        RECT 24.890 0.275 25.030 0.610 ;
        RECT 25.850 0.275 25.990 0.610 ;
        RECT 26.810 0.275 26.950 0.610 ;
        RECT 27.770 0.275 27.910 0.610 ;
        RECT 28.730 0.275 28.870 0.610 ;
        RECT 29.690 0.275 37.510 0.610 ;
        RECT 38.330 0.275 38.470 0.610 ;
        RECT 39.290 0.275 39.430 0.610 ;
        RECT 40.250 0.275 40.390 0.610 ;
        RECT 41.210 0.275 41.350 0.610 ;
        RECT 42.170 0.275 42.310 0.610 ;
        RECT 43.130 0.275 43.270 0.610 ;
        RECT 44.090 0.275 44.230 0.610 ;
        RECT 45.050 0.275 45.190 0.610 ;
        RECT 46.010 0.275 46.150 0.610 ;
        RECT 46.970 0.275 47.110 0.610 ;
        RECT 47.930 0.275 48.070 0.610 ;
        RECT 48.890 0.275 49.030 0.610 ;
        RECT 49.850 0.275 49.990 0.610 ;
        RECT 50.810 0.275 50.950 0.610 ;
        RECT 51.770 0.275 51.910 0.610 ;
        RECT 52.730 0.275 58.630 0.610 ;
        RECT 59.450 0.275 59.590 0.610 ;
        RECT 60.410 0.275 60.550 0.610 ;
        RECT 61.370 0.275 61.510 0.610 ;
        RECT 62.330 0.275 66.310 0.610 ;
        RECT 67.130 0.275 67.270 0.610 ;
        RECT 68.090 0.275 68.230 0.610 ;
        RECT 69.050 0.275 69.190 0.610 ;
        RECT 70.010 0.275 70.150 0.610 ;
        RECT 70.970 0.275 71.110 0.610 ;
        RECT 71.930 0.275 72.070 0.610 ;
        RECT 72.890 0.275 73.030 0.610 ;
        RECT 73.850 0.275 78.790 0.610 ;
        RECT 79.610 0.275 79.750 0.610 ;
        RECT 80.570 0.275 80.710 0.610 ;
        RECT 81.530 0.275 81.670 0.610 ;
        RECT 82.490 0.275 82.630 0.610 ;
        RECT 83.450 0.275 83.590 0.610 ;
        RECT 84.410 0.275 84.550 0.610 ;
        RECT 85.370 0.275 85.510 0.610 ;
        RECT 86.330 0.275 94.150 0.610 ;
        RECT 94.970 0.275 95.110 0.610 ;
        RECT 95.930 0.275 96.070 0.610 ;
        RECT 96.890 0.275 97.030 0.610 ;
        RECT 97.850 0.275 97.990 0.610 ;
        RECT 98.810 0.275 98.950 0.610 ;
        RECT 99.770 0.275 99.910 0.610 ;
        RECT 100.730 0.275 100.870 0.610 ;
        RECT 101.690 0.275 101.830 0.610 ;
        RECT 102.650 0.275 102.790 0.610 ;
        RECT 103.610 0.275 103.750 0.610 ;
        RECT 104.570 0.275 104.710 0.610 ;
        RECT 105.530 0.275 105.670 0.610 ;
        RECT 106.490 0.275 106.630 0.610 ;
        RECT 107.450 0.275 107.590 0.610 ;
        RECT 108.410 0.275 108.550 0.610 ;
        RECT 109.370 0.275 121.990 0.610 ;
        RECT 122.810 0.275 122.950 0.610 ;
        RECT 123.770 0.275 123.910 0.610 ;
        RECT 124.730 0.275 124.870 0.610 ;
        RECT 125.690 0.275 125.830 0.610 ;
        RECT 126.650 0.275 126.790 0.610 ;
        RECT 127.610 0.275 127.750 0.610 ;
        RECT 128.570 0.275 128.710 0.610 ;
        RECT 129.530 0.275 129.670 0.610 ;
        RECT 130.490 0.275 130.630 0.610 ;
        RECT 131.450 0.275 131.590 0.610 ;
        RECT 132.410 0.275 132.550 0.610 ;
        RECT 133.370 0.275 133.510 0.610 ;
        RECT 134.330 0.275 134.470 0.610 ;
        RECT 135.290 0.275 135.430 0.610 ;
        RECT 136.250 0.275 136.390 0.610 ;
        RECT 137.210 0.275 137.350 0.610 ;
        RECT 138.170 0.275 138.310 0.610 ;
        RECT 139.130 0.275 139.270 0.610 ;
        RECT 140.090 0.275 140.230 0.610 ;
        RECT 141.050 0.275 142.665 0.610 ;
      LAYER Metal3 ;
        RECT 0.400 41.990 146.980 53.860 ;
        RECT 0.610 41.170 146.750 41.990 ;
        RECT 0.400 41.150 146.980 41.170 ;
        RECT 0.610 40.330 146.750 41.150 ;
        RECT 0.400 40.310 146.980 40.330 ;
        RECT 0.610 39.490 146.750 40.310 ;
        RECT 0.400 39.470 146.980 39.490 ;
        RECT 0.610 38.650 146.750 39.470 ;
        RECT 0.400 38.630 146.980 38.650 ;
        RECT 0.610 37.810 146.750 38.630 ;
        RECT 0.400 37.790 146.980 37.810 ;
        RECT 0.610 36.970 146.750 37.790 ;
        RECT 0.400 36.950 146.980 36.970 ;
        RECT 0.610 36.130 146.750 36.950 ;
        RECT 0.400 36.110 146.980 36.130 ;
        RECT 0.610 35.290 146.750 36.110 ;
        RECT 0.400 35.270 146.980 35.290 ;
        RECT 0.610 34.450 146.750 35.270 ;
        RECT 0.400 34.430 146.980 34.450 ;
        RECT 0.610 33.610 146.750 34.430 ;
        RECT 0.400 33.590 146.980 33.610 ;
        RECT 0.610 32.770 146.750 33.590 ;
        RECT 0.400 32.750 146.980 32.770 ;
        RECT 0.610 31.930 146.750 32.750 ;
        RECT 0.400 31.910 146.980 31.930 ;
        RECT 0.610 31.090 146.750 31.910 ;
        RECT 0.400 31.070 146.980 31.090 ;
        RECT 0.610 30.250 146.750 31.070 ;
        RECT 0.400 30.230 146.980 30.250 ;
        RECT 0.610 29.410 146.750 30.230 ;
        RECT 0.400 29.390 146.980 29.410 ;
        RECT 0.610 28.570 146.750 29.390 ;
        RECT 0.400 28.550 146.980 28.570 ;
        RECT 0.610 27.730 146.750 28.550 ;
        RECT 0.400 27.710 146.980 27.730 ;
        RECT 0.610 26.890 146.750 27.710 ;
        RECT 0.400 26.870 146.980 26.890 ;
        RECT 0.610 26.050 146.750 26.870 ;
        RECT 0.400 26.030 146.980 26.050 ;
        RECT 0.610 25.210 146.750 26.030 ;
        RECT 0.400 25.190 146.980 25.210 ;
        RECT 0.610 24.370 146.750 25.190 ;
        RECT 0.400 24.350 146.980 24.370 ;
        RECT 0.610 23.530 146.750 24.350 ;
        RECT 0.400 23.510 146.980 23.530 ;
        RECT 0.610 22.690 146.750 23.510 ;
        RECT 0.400 22.670 146.980 22.690 ;
        RECT 0.610 21.850 146.750 22.670 ;
        RECT 0.400 21.830 146.980 21.850 ;
        RECT 0.610 21.010 146.750 21.830 ;
        RECT 0.400 20.990 146.980 21.010 ;
        RECT 0.610 20.170 146.750 20.990 ;
        RECT 0.400 20.150 146.980 20.170 ;
        RECT 0.610 19.330 146.750 20.150 ;
        RECT 0.400 19.310 146.980 19.330 ;
        RECT 0.610 18.490 146.750 19.310 ;
        RECT 0.400 18.470 146.980 18.490 ;
        RECT 0.610 17.650 146.750 18.470 ;
        RECT 0.400 17.630 146.980 17.650 ;
        RECT 0.610 16.810 146.750 17.630 ;
        RECT 0.400 16.790 146.980 16.810 ;
        RECT 0.610 15.970 146.750 16.790 ;
        RECT 0.400 15.950 146.980 15.970 ;
        RECT 0.610 15.130 146.750 15.950 ;
        RECT 0.400 1.670 146.980 15.130 ;
        RECT 0.610 0.850 146.750 1.670 ;
        RECT 0.400 0.315 146.980 0.850 ;
      LAYER Metal4 ;
        RECT 6.890 0.275 15.170 38.430 ;
        RECT 17.790 0.275 21.370 38.430 ;
        RECT 23.990 0.275 90.770 38.430 ;
        RECT 93.390 0.275 96.970 38.430 ;
        RECT 99.590 0.275 143.350 38.430 ;
      LAYER TopMetal1 ;
        RECT 6.380 7.660 143.860 38.940 ;
  END
END N_term_RAM_IO
END LIBRARY

